VERSION 5.7 ;
  NOWIREEXTENSIONATPIN ON ;
  DIVIDERCHAR "/" ;
  BUSBITCHARS "[]" ;
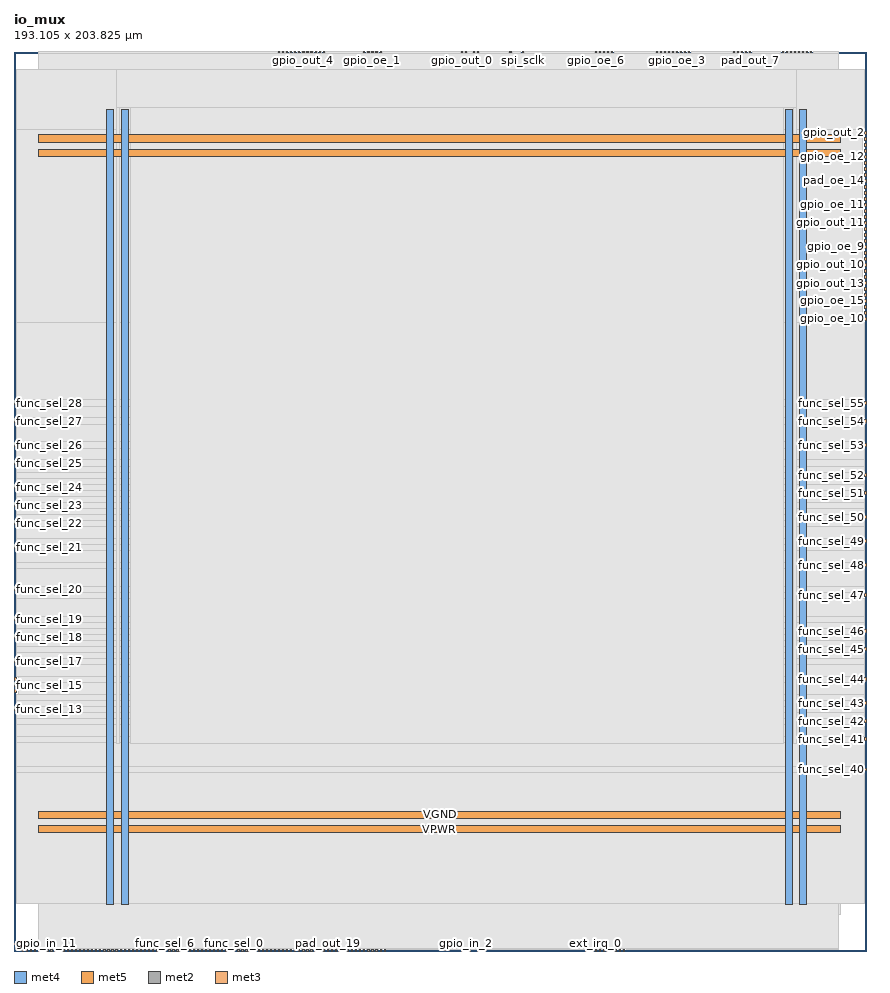
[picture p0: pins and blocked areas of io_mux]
MACRO io_mux
  CLASS BLOCK ;
  FOREIGN io_mux ;
  ORIGIN 0.000 0.000 ;
  SIZE 193.105 BY 203.825 ;
  PIN VGND
    DIRECTION INOUT ;
    USE GROUND ;
    PORT
      LAYER met4 ;
        RECT 24.340 10.640 25.940 190.640 ;
    END
    PORT
      LAYER met4 ;
        RECT 177.940 10.640 179.540 190.640 ;
    END
    PORT
      LAYER met5 ;
        RECT 5.520 30.030 187.220 31.630 ;
    END
    PORT
      LAYER met5 ;
        RECT 5.520 183.210 187.220 184.810 ;
    END
  END VGND
  PIN VPWR
    DIRECTION INOUT ;
    USE POWER ;
    PORT
      LAYER met4 ;
        RECT 21.040 10.640 22.640 190.640 ;
    END
    PORT
      LAYER met4 ;
        RECT 174.640 10.640 176.240 190.640 ;
    END
    PORT
      LAYER met5 ;
        RECT 5.520 26.730 187.220 28.330 ;
    END
    PORT
      LAYER met5 ;
        RECT 5.520 179.910 187.220 181.510 ;
    END
  END VPWR
  PIN ext_irq_0
    DIRECTION OUTPUT ;
    USE SIGNAL ;
    ANTENNAGATEAREA 0.434700 ;
    ANTENNADIFFAREA 0.775300 ;
    PORT
      LAYER met2 ;
        RECT 131.650 0.000 131.930 0.280 ;
    END
  END ext_irq_0
  PIN ext_irq_1
    DIRECTION OUTPUT ;
    USE SIGNAL ;
    ANTENNAGATEAREA 0.434700 ;
    ANTENNADIFFAREA 0.775300 ;
    PORT
      LAYER met2 ;
        RECT 138.090 0.000 138.370 0.280 ;
    END
  END ext_irq_1
  PIN ext_irq_2
    DIRECTION OUTPUT ;
    USE SIGNAL ;
    ANTENNAGATEAREA 0.434700 ;
    ANTENNADIFFAREA 0.775300 ;
    PORT
      LAYER met2 ;
        RECT 137.170 0.000 137.450 0.280 ;
    END
  END ext_irq_2
  PIN ext_irq_3
    DIRECTION OUTPUT ;
    USE SIGNAL ;
    ANTENNAGATEAREA 0.434700 ;
    ANTENNADIFFAREA 0.775300 ;
    PORT
      LAYER met2 ;
        RECT 133.490 0.000 133.770 0.280 ;
    END
  END ext_irq_3
  PIN ext_irq_4
    DIRECTION OUTPUT ;
    USE SIGNAL ;
    ANTENNAGATEAREA 0.434700 ;
    ANTENNADIFFAREA 0.775300 ;
    PORT
      LAYER met2 ;
        RECT 132.570 0.000 132.850 0.280 ;
    END
  END ext_irq_4
  PIN ext_irq_5
    DIRECTION OUTPUT ;
    USE SIGNAL ;
    ANTENNAGATEAREA 0.434700 ;
    ANTENNADIFFAREA 0.775300 ;
    PORT
      LAYER met2 ;
        RECT 134.410 0.000 134.690 0.280 ;
    END
  END ext_irq_5
  PIN ext_irq_6
    DIRECTION OUTPUT ;
    USE SIGNAL ;
    ANTENNAGATEAREA 0.434700 ;
    ANTENNADIFFAREA 0.775300 ;
    PORT
      LAYER met2 ;
        RECT 136.250 0.000 136.530 0.280 ;
    END
  END ext_irq_6
  PIN ext_irq_7
    DIRECTION OUTPUT ;
    USE SIGNAL ;
    ANTENNAGATEAREA 0.434700 ;
    ANTENNADIFFAREA 0.775300 ;
    PORT
      LAYER met2 ;
        RECT 135.330 0.000 135.610 0.280 ;
    END
  END ext_irq_7
  PIN func_sel_0
    DIRECTION INPUT ;
    USE SIGNAL ;
    ANTENNAGATEAREA 0.647700 ;
    ANTENNADIFFAREA 0.434700 ;
    PORT
      LAYER met2 ;
        RECT 49.770 0.000 50.050 0.280 ;
    END
  END func_sel_0
  PIN func_sel_1
    DIRECTION INPUT ;
    USE SIGNAL ;
    ANTENNAGATEAREA 0.647700 ;
    ANTENNADIFFAREA 0.434700 ;
    PORT
      LAYER met2 ;
        RECT 33.210 0.000 33.490 0.280 ;
    END
  END func_sel_1
  PIN func_sel_10
    DIRECTION INPUT ;
    USE SIGNAL ;
    ANTENNAGATEAREA 1.424700 ;
    ANTENNADIFFAREA 0.434700 ;
    PORT
      LAYER met2 ;
        RECT 23.090 0.000 23.370 0.280 ;
    END
  END func_sel_10
  PIN func_sel_11
    DIRECTION INPUT ;
    USE SIGNAL ;
    ANTENNAGATEAREA 1.424700 ;
    ANTENNADIFFAREA 0.434700 ;
    PORT
      LAYER met2 ;
        RECT 20.330 0.000 20.610 0.280 ;
    END
  END func_sel_11
  PIN func_sel_12
    DIRECTION INPUT ;
    USE SIGNAL ;
    ANTENNAGATEAREA 0.929700 ;
    ANTENNADIFFAREA 0.434700 ;
    PORT
      LAYER met2 ;
        RECT 18.490 0.000 18.770 0.280 ;
    END
  END func_sel_12
  PIN func_sel_13
    DIRECTION INPUT ;
    USE SIGNAL ;
    ANTENNAGATEAREA 0.929700 ;
    ANTENNADIFFAREA 0.434700 ;
    PORT
      LAYER met3 ;
        RECT 0.000 54.440 0.600 55.040 ;
    END
  END func_sel_13
  PIN func_sel_14
    DIRECTION INPUT ;
    USE SIGNAL ;
    ANTENNAGATEAREA 0.929700 ;
    ANTENNADIFFAREA 0.434700 ;
    PORT
      LAYER met3 ;
        RECT 0.000 61.240 0.600 61.840 ;
    END
  END func_sel_14
  PIN func_sel_15
    DIRECTION INPUT ;
    USE SIGNAL ;
    ANTENNAGATEAREA 0.647700 ;
    ANTENNADIFFAREA 0.434700 ;
    PORT
      LAYER met3 ;
        RECT 0.000 59.880 0.600 60.480 ;
    END
  END func_sel_15
  PIN func_sel_16
    DIRECTION INPUT ;
    USE SIGNAL ;
    ANTENNAGATEAREA 0.560700 ;
    ANTENNADIFFAREA 0.434700 ;
    PORT
      LAYER met3 ;
        RECT 0.000 58.520 0.600 59.120 ;
    END
  END func_sel_16
  PIN func_sel_17
    DIRECTION INPUT ;
    USE SIGNAL ;
    ANTENNAGATEAREA 0.647700 ;
    ANTENNADIFFAREA 0.434700 ;
    PORT
      LAYER met3 ;
        RECT 0.000 65.320 0.600 65.920 ;
    END
  END func_sel_17
  PIN func_sel_18
    DIRECTION INPUT ;
    USE SIGNAL ;
    ANTENNAGATEAREA 0.929700 ;
    ANTENNADIFFAREA 0.434700 ;
    PORT
      LAYER met3 ;
        RECT 0.000 70.760 0.600 71.360 ;
    END
  END func_sel_18
  PIN func_sel_19
    DIRECTION INPUT ;
    USE SIGNAL ;
    ANTENNAGATEAREA 0.647700 ;
    ANTENNADIFFAREA 0.434700 ;
    PORT
      LAYER met3 ;
        RECT 0.000 74.840 0.600 75.440 ;
    END
  END func_sel_19
  PIN func_sel_2
    DIRECTION INPUT ;
    USE SIGNAL ;
    ANTENNAGATEAREA 0.647700 ;
    ANTENNADIFFAREA 0.434700 ;
    PORT
      LAYER met2 ;
        RECT 42.410 0.000 42.690 0.280 ;
    END
  END func_sel_2
  PIN func_sel_20
    DIRECTION INPUT ;
    USE SIGNAL ;
    ANTENNAGATEAREA 0.929700 ;
    ANTENNADIFFAREA 0.434700 ;
    PORT
      LAYER met3 ;
        RECT 0.000 81.640 0.600 82.240 ;
    END
  END func_sel_20
  PIN func_sel_21
    DIRECTION INPUT ;
    USE SIGNAL ;
    ANTENNAGATEAREA 0.929700 ;
    ANTENNADIFFAREA 0.434700 ;
    PORT
      LAYER met3 ;
        RECT 0.000 91.160 0.600 91.760 ;
    END
  END func_sel_21
  PIN func_sel_22
    DIRECTION INPUT ;
    USE SIGNAL ;
    ANTENNAGATEAREA 0.682200 ;
    ANTENNADIFFAREA 0.434700 ;
    PORT
      LAYER met3 ;
        RECT 0.000 96.600 0.600 97.200 ;
    END
  END func_sel_22
  PIN func_sel_23
    DIRECTION INPUT ;
    USE SIGNAL ;
    ANTENNAGATEAREA 0.682200 ;
    ANTENNADIFFAREA 0.434700 ;
    PORT
      LAYER met3 ;
        RECT 0.000 100.680 0.600 101.280 ;
    END
  END func_sel_23
  PIN func_sel_24
    DIRECTION INPUT ;
    USE SIGNAL ;
    ANTENNAGATEAREA 0.593700 ;
    ANTENNADIFFAREA 0.434700 ;
    PORT
      LAYER met3 ;
        RECT 0.000 104.760 0.600 105.360 ;
    END
  END func_sel_24
  PIN func_sel_25
    DIRECTION INPUT ;
    USE SIGNAL ;
    ANTENNAGATEAREA 0.682200 ;
    ANTENNADIFFAREA 0.434700 ;
    PORT
      LAYER met3 ;
        RECT 0.000 110.200 0.600 110.800 ;
    END
  END func_sel_25
  PIN func_sel_26
    DIRECTION INPUT ;
    USE SIGNAL ;
    ANTENNAGATEAREA 0.682200 ;
    ANTENNADIFFAREA 0.434700 ;
    PORT
      LAYER met3 ;
        RECT 0.000 114.280 0.600 114.880 ;
    END
  END func_sel_26
  PIN func_sel_27
    DIRECTION INPUT ;
    USE SIGNAL ;
    ANTENNAGATEAREA 0.647700 ;
    ANTENNADIFFAREA 0.434700 ;
    PORT
      LAYER met3 ;
        RECT 0.000 119.720 0.600 120.320 ;
    END
  END func_sel_27
  PIN func_sel_28
    DIRECTION INPUT ;
    USE SIGNAL ;
    ANTENNAGATEAREA 0.929700 ;
    ANTENNADIFFAREA 0.434700 ;
    PORT
      LAYER met3 ;
        RECT 0.000 123.800 0.600 124.400 ;
    END
  END func_sel_28
  PIN func_sel_29
    DIRECTION INPUT ;
    USE SIGNAL ;
    ANTENNAGATEAREA 1.424700 ;
    ANTENNADIFFAREA 0.434700 ;
    PORT
      LAYER met2 ;
        RECT 35.050 0.000 35.330 0.280 ;
    END
  END func_sel_29
  PIN func_sel_3
    DIRECTION INPUT ;
    USE SIGNAL ;
    ANTENNAGATEAREA 0.929700 ;
    ANTENNADIFFAREA 0.434700 ;
    PORT
      LAYER met2 ;
        RECT 28.610 0.000 28.890 0.280 ;
    END
  END func_sel_3
  PIN func_sel_30
    DIRECTION INPUT ;
    USE SIGNAL ;
    ANTENNAGATEAREA 0.929700 ;
    ANTENNADIFFAREA 0.434700 ;
    PORT
      LAYER met2 ;
        RECT 39.650 0.000 39.930 0.280 ;
    END
  END func_sel_30
  PIN func_sel_31
    DIRECTION INPUT ;
    USE SIGNAL ;
    ANTENNAGATEAREA 0.929700 ;
    ANTENNADIFFAREA 0.434700 ;
    PORT
      LAYER met2 ;
        RECT 44.250 0.000 44.530 0.280 ;
    END
  END func_sel_31
  PIN func_sel_32
    DIRECTION INPUT ;
    USE SIGNAL ;
    ANTENNAGATEAREA 0.647700 ;
    ANTENNADIFFAREA 0.434700 ;
    PORT
      LAYER met2 ;
        RECT 47.930 0.000 48.210 0.280 ;
    END
  END func_sel_32
  PIN func_sel_33
    DIRECTION INPUT ;
    USE SIGNAL ;
    ANTENNAGATEAREA 0.647700 ;
    ANTENNADIFFAREA 0.434700 ;
    PORT
      LAYER met2 ;
        RECT 51.610 0.000 51.890 0.280 ;
    END
  END func_sel_33
  PIN func_sel_34
    DIRECTION INPUT ;
    USE SIGNAL ;
    ANTENNAGATEAREA 0.682200 ;
    ANTENNADIFFAREA 0.434700 ;
    PORT
      LAYER met2 ;
        RECT 55.290 0.000 55.570 0.280 ;
    END
  END func_sel_34
  PIN func_sel_35
    DIRECTION INPUT ;
    USE SIGNAL ;
    ANTENNAGATEAREA 0.647700 ;
    ANTENNADIFFAREA 0.434700 ;
    PORT
      LAYER met2 ;
        RECT 59.890 0.000 60.170 0.280 ;
    END
  END func_sel_35
  PIN func_sel_36
    DIRECTION INPUT ;
    USE SIGNAL ;
    ANTENNAGATEAREA 0.647700 ;
    ANTENNADIFFAREA 0.434700 ;
    PORT
      LAYER met2 ;
        RECT 63.570 0.000 63.850 0.280 ;
    END
  END func_sel_36
  PIN func_sel_37
    DIRECTION INPUT ;
    USE SIGNAL ;
    ANTENNAGATEAREA 0.560700 ;
    ANTENNADIFFAREA 0.434700 ;
    PORT
      LAYER met2 ;
        RECT 67.250 0.000 67.530 0.280 ;
    END
  END func_sel_37
  PIN func_sel_38
    DIRECTION INPUT ;
    USE SIGNAL ;
    ANTENNAGATEAREA 0.560700 ;
    ANTENNADIFFAREA 0.434700 ;
    PORT
      LAYER met2 ;
        RECT 70.010 0.000 70.290 0.280 ;
    END
  END func_sel_38
  PIN func_sel_39
    DIRECTION INPUT ;
    USE SIGNAL ;
    ANTENNAGATEAREA 0.647700 ;
    ANTENNADIFFAREA 0.434700 ;
    PORT
      LAYER met2 ;
        RECT 73.690 0.000 73.970 0.280 ;
    END
  END func_sel_39
  PIN func_sel_4
    DIRECTION INPUT ;
    USE SIGNAL ;
    ANTENNAGATEAREA 0.929700 ;
    ANTENNADIFFAREA 0.434700 ;
    PORT
      LAYER met2 ;
        RECT 43.330 0.000 43.610 0.280 ;
    END
  END func_sel_4
  PIN func_sel_40
    DIRECTION INPUT ;
    USE SIGNAL ;
    ANTENNAGATEAREA 0.647700 ;
    ANTENNADIFFAREA 0.434700 ;
    PORT
      LAYER met3 ;
        RECT 192.505 40.840 193.105 41.440 ;
    END
  END func_sel_40
  PIN func_sel_41
    DIRECTION INPUT ;
    USE SIGNAL ;
    ANTENNAGATEAREA 0.647700 ;
    ANTENNADIFFAREA 0.434700 ;
    PORT
      LAYER met3 ;
        RECT 192.505 47.640 193.105 48.240 ;
    END
  END func_sel_41
  PIN func_sel_42
    DIRECTION INPUT ;
    USE SIGNAL ;
    ANTENNAGATEAREA 0.647700 ;
    ANTENNADIFFAREA 0.434700 ;
    PORT
      LAYER met3 ;
        RECT 192.505 51.720 193.105 52.320 ;
    END
  END func_sel_42
  PIN func_sel_43
    DIRECTION INPUT ;
    USE SIGNAL ;
    ANTENNAGATEAREA 0.647700 ;
    ANTENNADIFFAREA 0.434700 ;
    PORT
      LAYER met3 ;
        RECT 192.505 55.800 193.105 56.400 ;
    END
  END func_sel_43
  PIN func_sel_44
    DIRECTION INPUT ;
    USE SIGNAL ;
    ANTENNAGATEAREA 0.647700 ;
    ANTENNADIFFAREA 0.434700 ;
    PORT
      LAYER met3 ;
        RECT 192.505 61.240 193.105 61.840 ;
    END
  END func_sel_44
  PIN func_sel_45
    DIRECTION INPUT ;
    USE SIGNAL ;
    ANTENNAGATEAREA 0.647700 ;
    ANTENNADIFFAREA 0.434700 ;
    PORT
      LAYER met3 ;
        RECT 192.505 68.040 193.105 68.640 ;
    END
  END func_sel_45
  PIN func_sel_46
    DIRECTION INPUT ;
    USE SIGNAL ;
    ANTENNAGATEAREA 0.647700 ;
    ANTENNADIFFAREA 0.434700 ;
    PORT
      LAYER met3 ;
        RECT 192.505 72.120 193.105 72.720 ;
    END
  END func_sel_46
  PIN func_sel_47
    DIRECTION INPUT ;
    USE SIGNAL ;
    ANTENNAGATEAREA 0.647700 ;
    ANTENNADIFFAREA 0.434700 ;
    PORT
      LAYER met3 ;
        RECT 192.505 80.280 193.105 80.880 ;
    END
  END func_sel_47
  PIN func_sel_48
    DIRECTION INPUT ;
    USE SIGNAL ;
    ANTENNAGATEAREA 0.647700 ;
    ANTENNADIFFAREA 0.434700 ;
    PORT
      LAYER met3 ;
        RECT 192.505 87.080 193.105 87.680 ;
    END
  END func_sel_48
  PIN func_sel_49
    DIRECTION INPUT ;
    USE SIGNAL ;
    ANTENNAGATEAREA 0.647700 ;
    ANTENNADIFFAREA 0.434700 ;
    PORT
      LAYER met3 ;
        RECT 192.505 92.520 193.105 93.120 ;
    END
  END func_sel_49
  PIN func_sel_5
    DIRECTION INPUT ;
    USE SIGNAL ;
    ANTENNAGATEAREA 0.929700 ;
    ANTENNADIFFAREA 0.434700 ;
    PORT
      LAYER met2 ;
        RECT 41.490 0.000 41.770 0.280 ;
    END
  END func_sel_5
  PIN func_sel_50
    DIRECTION INPUT ;
    USE SIGNAL ;
    ANTENNAGATEAREA 0.647700 ;
    ANTENNADIFFAREA 0.434700 ;
    PORT
      LAYER met3 ;
        RECT 192.505 97.960 193.105 98.560 ;
    END
  END func_sel_50
  PIN func_sel_51
    DIRECTION INPUT ;
    USE SIGNAL ;
    ANTENNAGATEAREA 0.647700 ;
    ANTENNADIFFAREA 0.434700 ;
    PORT
      LAYER met3 ;
        RECT 192.505 103.400 193.105 104.000 ;
    END
  END func_sel_51
  PIN func_sel_52
    DIRECTION INPUT ;
    USE SIGNAL ;
    ANTENNAGATEAREA 0.647700 ;
    ANTENNADIFFAREA 0.434700 ;
    PORT
      LAYER met3 ;
        RECT 192.505 107.480 193.105 108.080 ;
    END
  END func_sel_52
  PIN func_sel_53
    DIRECTION INPUT ;
    USE SIGNAL ;
    ANTENNAGATEAREA 0.647700 ;
    ANTENNADIFFAREA 0.434700 ;
    PORT
      LAYER met3 ;
        RECT 192.505 114.280 193.105 114.880 ;
    END
  END func_sel_53
  PIN func_sel_54
    DIRECTION INPUT ;
    USE SIGNAL ;
    ANTENNAGATEAREA 0.647700 ;
    ANTENNADIFFAREA 0.434700 ;
    PORT
      LAYER met3 ;
        RECT 192.505 119.720 193.105 120.320 ;
    END
  END func_sel_54
  PIN func_sel_55
    DIRECTION INPUT ;
    USE SIGNAL ;
    ANTENNAGATEAREA 0.647700 ;
    ANTENNADIFFAREA 0.434700 ;
    PORT
      LAYER met3 ;
        RECT 192.505 123.800 193.105 124.400 ;
    END
  END func_sel_55
  PIN func_sel_56
    DIRECTION INPUT ;
    USE SIGNAL ;
    ANTENNAGATEAREA 0.647700 ;
    ANTENNADIFFAREA 0.434700 ;
    PORT
      LAYER met2 ;
        RECT 180.410 203.545 180.690 203.825 ;
    END
  END func_sel_56
  PIN func_sel_57
    DIRECTION INPUT ;
    USE SIGNAL ;
    ANTENNAGATEAREA 0.647700 ;
    ANTENNADIFFAREA 0.434700 ;
    PORT
      LAYER met2 ;
        RECT 179.490 203.545 179.770 203.825 ;
    END
  END func_sel_57
  PIN func_sel_58
    DIRECTION INPUT ;
    USE SIGNAL ;
    ANTENNAGATEAREA 0.647700 ;
    ANTENNADIFFAREA 0.434700 ;
    PORT
      LAYER met2 ;
        RECT 178.570 203.545 178.850 203.825 ;
    END
  END func_sel_58
  PIN func_sel_59
    DIRECTION INPUT ;
    USE SIGNAL ;
    ANTENNAGATEAREA 0.647700 ;
    ANTENNADIFFAREA 0.434700 ;
    PORT
      LAYER met2 ;
        RECT 177.650 203.545 177.930 203.825 ;
    END
  END func_sel_59
  PIN func_sel_6
    DIRECTION INPUT ;
    USE SIGNAL ;
    ANTENNAGATEAREA 0.682200 ;
    ANTENNADIFFAREA 0.434700 ;
    PORT
      LAYER met2 ;
        RECT 34.130 0.000 34.410 0.280 ;
    END
  END func_sel_6
  PIN func_sel_60
    DIRECTION INPUT ;
    USE SIGNAL ;
    ANTENNAGATEAREA 0.647700 ;
    ANTENNADIFFAREA 0.434700 ;
    PORT
      LAYER met2 ;
        RECT 176.730 203.545 177.010 203.825 ;
    END
  END func_sel_60
  PIN func_sel_61
    DIRECTION INPUT ;
    USE SIGNAL ;
    ANTENNAGATEAREA 0.647700 ;
    ANTENNADIFFAREA 0.434700 ;
    PORT
      LAYER met2 ;
        RECT 175.810 203.545 176.090 203.825 ;
    END
  END func_sel_61
  PIN func_sel_62
    DIRECTION INPUT ;
    USE SIGNAL ;
    ANTENNAGATEAREA 0.647700 ;
    ANTENNADIFFAREA 0.434700 ;
    PORT
      LAYER met2 ;
        RECT 174.890 203.545 175.170 203.825 ;
    END
  END func_sel_62
  PIN func_sel_63
    DIRECTION INPUT ;
    USE SIGNAL ;
    ANTENNAGATEAREA 0.647700 ;
    ANTENNADIFFAREA 0.434700 ;
    PORT
      LAYER met2 ;
        RECT 173.970 203.545 174.250 203.825 ;
    END
  END func_sel_63
  PIN func_sel_7
    DIRECTION INPUT ;
    USE SIGNAL ;
    ANTENNAGATEAREA 0.682200 ;
    ANTENNADIFFAREA 0.434700 ;
    PORT
      LAYER met2 ;
        RECT 35.970 0.000 36.250 0.280 ;
    END
  END func_sel_7
  PIN func_sel_8
    DIRECTION INPUT ;
    USE SIGNAL ;
    ANTENNAGATEAREA 0.929700 ;
    ANTENNADIFFAREA 0.434700 ;
    PORT
      LAYER met2 ;
        RECT 26.770 0.000 27.050 0.280 ;
    END
  END func_sel_8
  PIN func_sel_9
    DIRECTION INPUT ;
    USE SIGNAL ;
    ANTENNAGATEAREA 0.647700 ;
    ANTENNADIFFAREA 0.434700 ;
    PORT
      LAYER met2 ;
        RECT 24.930 0.000 25.210 0.280 ;
    END
  END func_sel_9
  PIN gpio_in_0
    DIRECTION OUTPUT ;
    USE SIGNAL ;
    PORT
      LAYER met2 ;
        RECT 1.930 0.000 2.210 0.280 ;
    END
  END gpio_in_0
  PIN gpio_in_1
    DIRECTION OUTPUT ;
    USE SIGNAL ;
    PORT
      LAYER met2 ;
        RECT 2.850 0.000 3.130 0.280 ;
    END
  END gpio_in_1
  PIN gpio_in_10
    DIRECTION OUTPUT ;
    USE SIGNAL ;
    PORT
      LAYER met2 ;
        RECT 3.770 0.000 4.050 0.280 ;
    END
  END gpio_in_10
  PIN gpio_in_11
    DIRECTION OUTPUT ;
    USE SIGNAL ;
    PORT
      LAYER met2 ;
        RECT 4.690 0.000 4.970 0.280 ;
    END
  END gpio_in_11
  PIN gpio_in_12
    DIRECTION OUTPUT ;
    USE SIGNAL ;
    PORT
      LAYER met2 ;
        RECT 5.610 0.000 5.890 0.280 ;
    END
  END gpio_in_12
  PIN gpio_in_13
    DIRECTION OUTPUT ;
    USE SIGNAL ;
    PORT
      LAYER met2 ;
        RECT 6.530 0.000 6.810 0.280 ;
    END
  END gpio_in_13
  PIN gpio_in_14
    DIRECTION OUTPUT ;
    USE SIGNAL ;
    PORT
      LAYER met2 ;
        RECT 7.450 0.000 7.730 0.280 ;
    END
  END gpio_in_14
  PIN gpio_in_15
    DIRECTION OUTPUT ;
    USE SIGNAL ;
    PORT
      LAYER met2 ;
        RECT 8.370 0.000 8.650 0.280 ;
    END
  END gpio_in_15
  PIN gpio_in_16
    DIRECTION OUTPUT ;
    USE SIGNAL ;
    PORT
      LAYER met2 ;
        RECT 9.290 0.000 9.570 0.280 ;
    END
  END gpio_in_16
  PIN gpio_in_17
    DIRECTION OUTPUT ;
    USE SIGNAL ;
    PORT
      LAYER met2 ;
        RECT 10.210 0.000 10.490 0.280 ;
    END
  END gpio_in_17
  PIN gpio_in_18
    DIRECTION OUTPUT ;
    USE SIGNAL ;
    PORT
      LAYER met2 ;
        RECT 11.130 0.000 11.410 0.280 ;
    END
  END gpio_in_18
  PIN gpio_in_19
    DIRECTION OUTPUT ;
    USE SIGNAL ;
    PORT
      LAYER met2 ;
        RECT 12.050 0.000 12.330 0.280 ;
    END
  END gpio_in_19
  PIN gpio_in_2
    DIRECTION OUTPUT ;
    USE SIGNAL ;
    ANTENNAGATEAREA 0.434700 ;
    ANTENNADIFFAREA 1.137600 ;
    PORT
      LAYER met2 ;
        RECT 102.210 0.000 102.490 0.280 ;
    END
  END gpio_in_2
  PIN gpio_in_20
    DIRECTION OUTPUT ;
    USE SIGNAL ;
    PORT
      LAYER met2 ;
        RECT 12.970 0.000 13.250 0.280 ;
    END
  END gpio_in_20
  PIN gpio_in_21
    DIRECTION OUTPUT ;
    USE SIGNAL ;
    PORT
      LAYER met2 ;
        RECT 13.890 0.000 14.170 0.280 ;
    END
  END gpio_in_21
  PIN gpio_in_22
    DIRECTION OUTPUT ;
    USE SIGNAL ;
    PORT
      LAYER met2 ;
        RECT 14.810 0.000 15.090 0.280 ;
    END
  END gpio_in_22
  PIN gpio_in_23
    DIRECTION OUTPUT ;
    USE SIGNAL ;
    PORT
      LAYER met2 ;
        RECT 15.730 0.000 16.010 0.280 ;
    END
  END gpio_in_23
  PIN gpio_in_24
    DIRECTION OUTPUT ;
    USE SIGNAL ;
    PORT
      LAYER met2 ;
        RECT 16.650 0.000 16.930 0.280 ;
    END
  END gpio_in_24
  PIN gpio_in_25
    DIRECTION OUTPUT ;
    USE SIGNAL ;
    PORT
      LAYER met2 ;
        RECT 17.570 0.000 17.850 0.280 ;
    END
  END gpio_in_25
  PIN gpio_in_26
    DIRECTION OUTPUT ;
    USE SIGNAL ;
    PORT
      LAYER met2 ;
        RECT 19.410 0.000 19.690 0.280 ;
    END
  END gpio_in_26
  PIN gpio_in_27
    DIRECTION OUTPUT ;
    USE SIGNAL ;
    PORT
      LAYER met2 ;
        RECT 21.250 0.000 21.530 0.280 ;
    END
  END gpio_in_27
  PIN gpio_in_28
    DIRECTION OUTPUT ;
    USE SIGNAL ;
    PORT
      LAYER met2 ;
        RECT 22.170 0.000 22.450 0.280 ;
    END
  END gpio_in_28
  PIN gpio_in_29
    DIRECTION OUTPUT ;
    USE SIGNAL ;
    PORT
      LAYER met2 ;
        RECT 24.010 0.000 24.290 0.280 ;
    END
  END gpio_in_29
  PIN gpio_in_3
    DIRECTION OUTPUT ;
    USE SIGNAL ;
    PORT
      LAYER met2 ;
        RECT 25.850 0.000 26.130 0.280 ;
    END
  END gpio_in_3
  PIN gpio_in_30
    DIRECTION OUTPUT ;
    USE SIGNAL ;
    PORT
      LAYER met2 ;
        RECT 27.690 0.000 27.970 0.280 ;
    END
  END gpio_in_30
  PIN gpio_in_31
    DIRECTION OUTPUT ;
    USE SIGNAL ;
    PORT
      LAYER met2 ;
        RECT 29.530 0.000 29.810 0.280 ;
    END
  END gpio_in_31
  PIN gpio_in_4
    DIRECTION OUTPUT ;
    USE SIGNAL ;
    PORT
      LAYER met2 ;
        RECT 30.450 0.000 30.730 0.280 ;
    END
  END gpio_in_4
  PIN gpio_in_5
    DIRECTION OUTPUT ;
    USE SIGNAL ;
    PORT
      LAYER met2 ;
        RECT 31.370 0.000 31.650 0.280 ;
    END
  END gpio_in_5
  PIN gpio_in_6
    DIRECTION OUTPUT ;
    USE SIGNAL ;
    PORT
      LAYER met2 ;
        RECT 32.290 0.000 32.570 0.280 ;
    END
  END gpio_in_6
  PIN gpio_in_7
    DIRECTION OUTPUT ;
    USE SIGNAL ;
    PORT
      LAYER met2 ;
        RECT 36.890 0.000 37.170 0.280 ;
    END
  END gpio_in_7
  PIN gpio_in_8
    DIRECTION OUTPUT ;
    USE SIGNAL ;
    PORT
      LAYER met2 ;
        RECT 37.810 0.000 38.090 0.280 ;
    END
  END gpio_in_8
  PIN gpio_in_9
    DIRECTION OUTPUT ;
    USE SIGNAL ;
    PORT
      LAYER met2 ;
        RECT 38.730 0.000 39.010 0.280 ;
    END
  END gpio_in_9
  PIN gpio_oe_0
    DIRECTION INPUT ;
    USE SIGNAL ;
    ANTENNAGATEAREA 0.647700 ;
    ANTENNADIFFAREA 0.434700 ;
    PORT
      LAYER met2 ;
        RECT 104.970 203.545 105.250 203.825 ;
    END
  END gpio_oe_0
  PIN gpio_oe_1
    DIRECTION INPUT ;
    USE SIGNAL ;
    ANTENNAGATEAREA 0.647700 ;
    ANTENNADIFFAREA 0.434700 ;
    PORT
      LAYER met2 ;
        RECT 81.050 203.545 81.330 203.825 ;
    END
  END gpio_oe_1
  PIN gpio_oe_10
    DIRECTION INPUT ;
    USE SIGNAL ;
    ANTENNAGATEAREA 0.647700 ;
    ANTENNADIFFAREA 0.434700 ;
    PORT
      LAYER met3 ;
        RECT 192.505 142.840 193.105 143.440 ;
    END
  END gpio_oe_10
  PIN gpio_oe_11
    DIRECTION INPUT ;
    USE SIGNAL ;
    ANTENNAGATEAREA 0.647700 ;
    ANTENNADIFFAREA 0.434700 ;
    PORT
      LAYER met3 ;
        RECT 192.505 168.680 193.105 169.280 ;
    END
  END gpio_oe_11
  PIN gpio_oe_12
    DIRECTION INPUT ;
    USE SIGNAL ;
    ANTENNAGATEAREA 0.647700 ;
    ANTENNADIFFAREA 0.434700 ;
    PORT
      LAYER met3 ;
        RECT 192.505 179.560 193.105 180.160 ;
    END
  END gpio_oe_12
  PIN gpio_oe_13
    DIRECTION INPUT ;
    USE SIGNAL ;
    ANTENNAGATEAREA 0.647700 ;
    ANTENNADIFFAREA 0.434700 ;
    PORT
      LAYER met3 ;
        RECT 192.505 149.640 193.105 150.240 ;
    END
  END gpio_oe_13
  PIN gpio_oe_14
    DIRECTION INPUT ;
    USE SIGNAL ;
    ANTENNAGATEAREA 0.647700 ;
    ANTENNADIFFAREA 0.434700 ;
    PORT
      LAYER met3 ;
        RECT 192.505 172.760 193.105 173.360 ;
    END
  END gpio_oe_14
  PIN gpio_oe_15
    DIRECTION INPUT ;
    USE SIGNAL ;
    ANTENNAGATEAREA 0.647700 ;
    ANTENNADIFFAREA 0.434700 ;
    PORT
      LAYER met3 ;
        RECT 192.505 145.560 193.105 146.160 ;
    END
  END gpio_oe_15
  PIN gpio_oe_2
    DIRECTION INPUT ;
    USE SIGNAL ;
    ANTENNAGATEAREA 0.647700 ;
    ANTENNADIFFAREA 0.434700 ;
    PORT
      LAYER met3 ;
        RECT 192.505 180.920 193.105 181.520 ;
    END
  END gpio_oe_2
  PIN gpio_oe_3
    DIRECTION INPUT ;
    USE SIGNAL ;
    ANTENNAGATEAREA 0.647700 ;
    ANTENNADIFFAREA 0.434700 ;
    PORT
      LAYER met2 ;
        RECT 150.050 203.545 150.330 203.825 ;
    END
  END gpio_oe_3
  PIN gpio_oe_4
    DIRECTION INPUT ;
    USE SIGNAL ;
    ANTENNAGATEAREA 0.647700 ;
    ANTENNADIFFAREA 0.434700 ;
    PORT
      LAYER met2 ;
        RECT 69.090 203.545 69.370 203.825 ;
    END
  END gpio_oe_4
  PIN gpio_oe_5
    DIRECTION INPUT ;
    USE SIGNAL ;
    ANTENNAGATEAREA 0.647700 ;
    ANTENNADIFFAREA 0.434700 ;
    PORT
      LAYER met2 ;
        RECT 67.250 203.545 67.530 203.825 ;
    END
  END gpio_oe_5
  PIN gpio_oe_6
    DIRECTION INPUT ;
    USE SIGNAL ;
    ANTENNAGATEAREA 0.647700 ;
    ANTENNADIFFAREA 0.434700 ;
    PORT
      LAYER met2 ;
        RECT 131.650 203.545 131.930 203.825 ;
    END
  END gpio_oe_6
  PIN gpio_oe_7
    DIRECTION INPUT ;
    USE SIGNAL ;
    ANTENNAGATEAREA 0.647700 ;
    ANTENNADIFFAREA 0.434700 ;
    PORT
      LAYER met2 ;
        RECT 165.690 203.545 165.970 203.825 ;
    END
  END gpio_oe_7
  PIN gpio_oe_8
    DIRECTION INPUT ;
    USE SIGNAL ;
    ANTENNAGATEAREA 0.647700 ;
    ANTENNADIFFAREA 0.434700 ;
    PORT
      LAYER met2 ;
        RECT 148.210 203.545 148.490 203.825 ;
    END
  END gpio_oe_8
  PIN gpio_oe_9
    DIRECTION INPUT ;
    USE SIGNAL ;
    ANTENNAGATEAREA 0.647700 ;
    ANTENNADIFFAREA 0.434700 ;
    PORT
      LAYER met3 ;
        RECT 192.505 159.160 193.105 159.760 ;
    END
  END gpio_oe_9
  PIN gpio_out_0
    DIRECTION INPUT ;
    USE SIGNAL ;
    ANTENNAGATEAREA 0.647700 ;
    ANTENNADIFFAREA 0.434700 ;
    PORT
      LAYER met2 ;
        RECT 101.290 203.545 101.570 203.825 ;
    END
  END gpio_out_0
  PIN gpio_out_1
    DIRECTION INPUT ;
    USE SIGNAL ;
    ANTENNAGATEAREA 0.647700 ;
    ANTENNADIFFAREA 0.434700 ;
    PORT
      LAYER met2 ;
        RECT 82.890 203.545 83.170 203.825 ;
    END
  END gpio_out_1
  PIN gpio_out_10
    DIRECTION INPUT ;
    USE SIGNAL ;
    ANTENNAGATEAREA 0.647700 ;
    ANTENNADIFFAREA 0.434700 ;
    PORT
      LAYER met3 ;
        RECT 192.505 155.080 193.105 155.680 ;
    END
  END gpio_out_10
  PIN gpio_out_11
    DIRECTION INPUT ;
    USE SIGNAL ;
    ANTENNAGATEAREA 0.647700 ;
    ANTENNADIFFAREA 0.434700 ;
    PORT
      LAYER met3 ;
        RECT 192.505 164.600 193.105 165.200 ;
    END
  END gpio_out_11
  PIN gpio_out_12
    DIRECTION INPUT ;
    USE SIGNAL ;
    ANTENNAGATEAREA 0.647700 ;
    ANTENNADIFFAREA 0.434700 ;
    PORT
      LAYER met3 ;
        RECT 192.505 178.200 193.105 178.800 ;
    END
  END gpio_out_12
  PIN gpio_out_13
    DIRECTION INPUT ;
    USE SIGNAL ;
    ANTENNAGATEAREA 0.647700 ;
    ANTENNADIFFAREA 0.434700 ;
    PORT
      LAYER met3 ;
        RECT 192.505 152.360 193.105 152.960 ;
    END
  END gpio_out_13
  PIN gpio_out_14
    DIRECTION INPUT ;
    USE SIGNAL ;
    ANTENNAGATEAREA 0.647700 ;
    ANTENNADIFFAREA 0.434700 ;
    PORT
      LAYER met3 ;
        RECT 192.505 170.040 193.105 170.640 ;
    END
  END gpio_out_14
  PIN gpio_out_15
    DIRECTION INPUT ;
    USE SIGNAL ;
    ANTENNAGATEAREA 0.647700 ;
    ANTENNADIFFAREA 0.434700 ;
    PORT
      LAYER met3 ;
        RECT 192.505 156.440 193.105 157.040 ;
    END
  END gpio_out_15
  PIN gpio_out_2
    DIRECTION INPUT ;
    USE SIGNAL ;
    ANTENNAGATEAREA 0.647700 ;
    ANTENNADIFFAREA 0.434700 ;
    PORT
      LAYER met3 ;
        RECT 192.505 185.000 193.105 185.600 ;
    END
  END gpio_out_2
  PIN gpio_out_3
    DIRECTION INPUT ;
    USE SIGNAL ;
    ANTENNAGATEAREA 0.647700 ;
    ANTENNADIFFAREA 0.434700 ;
    PORT
      LAYER met2 ;
        RECT 152.810 203.545 153.090 203.825 ;
    END
  END gpio_out_3
  PIN gpio_out_4
    DIRECTION INPUT ;
    USE SIGNAL ;
    ANTENNAGATEAREA 0.647700 ;
    ANTENNADIFFAREA 0.434700 ;
    PORT
      LAYER met2 ;
        RECT 65.410 203.545 65.690 203.825 ;
    END
  END gpio_out_4
  PIN gpio_out_5
    DIRECTION INPUT ;
    USE SIGNAL ;
    ANTENNAGATEAREA 0.647700 ;
    ANTENNADIFFAREA 0.434700 ;
    PORT
      LAYER met2 ;
        RECT 66.330 203.545 66.610 203.825 ;
    END
  END gpio_out_5
  PIN gpio_out_6
    DIRECTION INPUT ;
    USE SIGNAL ;
    ANTENNAGATEAREA 0.647700 ;
    ANTENNADIFFAREA 0.434700 ;
    PORT
      LAYER met2 ;
        RECT 134.410 203.545 134.690 203.825 ;
    END
  END gpio_out_6
  PIN gpio_out_7
    DIRECTION INPUT ;
    USE SIGNAL ;
    ANTENNAGATEAREA 0.647700 ;
    ANTENNADIFFAREA 0.434700 ;
    PORT
      LAYER met2 ;
        RECT 164.770 203.545 165.050 203.825 ;
    END
  END gpio_out_7
  PIN gpio_out_8
    DIRECTION INPUT ;
    USE SIGNAL ;
    ANTENNAGATEAREA 0.647700 ;
    ANTENNADIFFAREA 0.434700 ;
    PORT
      LAYER met2 ;
        RECT 149.130 203.545 149.410 203.825 ;
    END
  END gpio_out_8
  PIN gpio_out_9
    DIRECTION INPUT ;
    USE SIGNAL ;
    ANTENNAGATEAREA 0.647700 ;
    ANTENNADIFFAREA 0.434700 ;
    PORT
      LAYER met3 ;
        RECT 192.505 160.520 193.105 161.120 ;
    END
  END gpio_out_9
  PIN i2c_scl_in
    DIRECTION OUTPUT ;
    USE SIGNAL ;
    PORT
      LAYER met2 ;
        RECT 40.570 0.000 40.850 0.280 ;
    END
  END i2c_scl_in
  PIN i2c_scl_oe
    DIRECTION INPUT ;
    USE SIGNAL ;
    ANTENNAGATEAREA 0.647700 ;
    ANTENNADIFFAREA 0.434700 ;
    PORT
      LAYER met2 ;
        RECT 59.890 203.545 60.170 203.825 ;
    END
  END i2c_scl_oe
  PIN i2c_scl_out
    DIRECTION INPUT ;
    USE SIGNAL ;
    ANTENNAGATEAREA 0.647700 ;
    ANTENNADIFFAREA 0.434700 ;
    PORT
      LAYER met2 ;
        RECT 61.730 203.545 62.010 203.825 ;
    END
  END i2c_scl_out
  PIN i2c_sda_in
    DIRECTION OUTPUT ;
    USE SIGNAL ;
    PORT
      LAYER met2 ;
        RECT 45.170 0.000 45.450 0.280 ;
    END
  END i2c_sda_in
  PIN i2c_sda_oe
    DIRECTION INPUT ;
    USE SIGNAL ;
    ANTENNAGATEAREA 0.647700 ;
    ANTENNADIFFAREA 0.434700 ;
    PORT
      LAYER met2 ;
        RECT 60.810 203.545 61.090 203.825 ;
    END
  END i2c_sda_oe
  PIN i2c_sda_out
    DIRECTION INPUT ;
    USE SIGNAL ;
    ANTENNAGATEAREA 0.647700 ;
    ANTENNADIFFAREA 0.434700 ;
    PORT
      LAYER met2 ;
        RECT 62.650 203.545 62.930 203.825 ;
    END
  END i2c_sda_out
  PIN pad_oe_0
    DIRECTION OUTPUT ;
    USE SIGNAL ;
    ANTENNAGATEAREA 0.434700 ;
    ANTENNADIFFAREA 1.771200 ;
    PORT
      LAYER met2 ;
        RECT 104.050 203.545 104.330 203.825 ;
    END
  END pad_oe_0
  PIN pad_oe_1
    DIRECTION OUTPUT ;
    USE SIGNAL ;
    ANTENNAGATEAREA 0.434700 ;
    ANTENNADIFFAREA 1.771200 ;
    PORT
      LAYER met2 ;
        RECT 79.210 203.545 79.490 203.825 ;
    END
  END pad_oe_1
  PIN pad_oe_10
    DIRECTION OUTPUT ;
    USE SIGNAL ;
    ANTENNAGATEAREA 0.434700 ;
    ANTENNADIFFAREA 2.216700 ;
    PORT
      LAYER met3 ;
        RECT 192.505 148.280 193.105 148.880 ;
    END
  END pad_oe_10
  PIN pad_oe_11
    DIRECTION OUTPUT ;
    USE SIGNAL ;
    ANTENNAGATEAREA 0.434700 ;
    ANTENNADIFFAREA 2.216700 ;
    PORT
      LAYER met3 ;
        RECT 192.505 167.320 193.105 167.920 ;
    END
  END pad_oe_11
  PIN pad_oe_12
    DIRECTION OUTPUT ;
    USE SIGNAL ;
    ANTENNAGATEAREA 0.434700 ;
    ANTENNADIFFAREA 1.325700 ;
    PORT
      LAYER met3 ;
        RECT 192.505 175.480 193.105 176.080 ;
    END
  END pad_oe_12
  PIN pad_oe_13
    DIRECTION OUTPUT ;
    USE SIGNAL ;
    ANTENNAGATEAREA 0.434700 ;
    ANTENNADIFFAREA 2.216700 ;
    PORT
      LAYER met3 ;
        RECT 192.505 151.000 193.105 151.600 ;
    END
  END pad_oe_13
  PIN pad_oe_14
    DIRECTION OUTPUT ;
    USE SIGNAL ;
    ANTENNAGATEAREA 0.434700 ;
    ANTENNADIFFAREA 2.216700 ;
    PORT
      LAYER met3 ;
        RECT 192.505 174.120 193.105 174.720 ;
    END
  END pad_oe_14
  PIN pad_oe_15
    DIRECTION OUTPUT ;
    USE SIGNAL ;
    ANTENNAGATEAREA 0.434700 ;
    ANTENNADIFFAREA 1.325700 ;
    PORT
      LAYER met3 ;
        RECT 192.505 144.200 193.105 144.800 ;
    END
  END pad_oe_15
  PIN pad_oe_16
    DIRECTION OUTPUT ;
    USE SIGNAL ;
    PORT
      LAYER met2 ;
        RECT 46.090 0.000 46.370 0.280 ;
    END
  END pad_oe_16
  PIN pad_oe_17
    DIRECTION OUTPUT ;
    USE SIGNAL ;
    PORT
      LAYER met2 ;
        RECT 47.010 0.000 47.290 0.280 ;
    END
  END pad_oe_17
  PIN pad_oe_18
    DIRECTION OUTPUT ;
    USE SIGNAL ;
    PORT
      LAYER met2 ;
        RECT 48.850 0.000 49.130 0.280 ;
    END
  END pad_oe_18
  PIN pad_oe_19
    DIRECTION OUTPUT ;
    USE SIGNAL ;
    PORT
      LAYER met2 ;
        RECT 50.690 0.000 50.970 0.280 ;
    END
  END pad_oe_19
  PIN pad_oe_2
    DIRECTION OUTPUT ;
    USE SIGNAL ;
    ANTENNAGATEAREA 0.434700 ;
    ANTENNADIFFAREA 1.771200 ;
    PORT
      LAYER met3 ;
        RECT 192.505 182.280 193.105 182.880 ;
    END
  END pad_oe_2
  PIN pad_oe_20
    DIRECTION OUTPUT ;
    USE SIGNAL ;
    PORT
      LAYER met2 ;
        RECT 52.530 0.000 52.810 0.280 ;
    END
  END pad_oe_20
  PIN pad_oe_21
    DIRECTION OUTPUT ;
    USE SIGNAL ;
    PORT
      LAYER met2 ;
        RECT 53.450 0.000 53.730 0.280 ;
    END
  END pad_oe_21
  PIN pad_oe_22
    DIRECTION OUTPUT ;
    USE SIGNAL ;
    PORT
      LAYER met2 ;
        RECT 54.370 0.000 54.650 0.280 ;
    END
  END pad_oe_22
  PIN pad_oe_23
    DIRECTION OUTPUT ;
    USE SIGNAL ;
    PORT
      LAYER met2 ;
        RECT 56.210 0.000 56.490 0.280 ;
    END
  END pad_oe_23
  PIN pad_oe_24
    DIRECTION OUTPUT ;
    USE SIGNAL ;
    PORT
      LAYER met2 ;
        RECT 57.130 0.000 57.410 0.280 ;
    END
  END pad_oe_24
  PIN pad_oe_25
    DIRECTION OUTPUT ;
    USE SIGNAL ;
    PORT
      LAYER met2 ;
        RECT 58.050 0.000 58.330 0.280 ;
    END
  END pad_oe_25
  PIN pad_oe_26
    DIRECTION OUTPUT ;
    USE SIGNAL ;
    PORT
      LAYER met2 ;
        RECT 58.970 0.000 59.250 0.280 ;
    END
  END pad_oe_26
  PIN pad_oe_27
    DIRECTION OUTPUT ;
    USE SIGNAL ;
    PORT
      LAYER met2 ;
        RECT 60.810 0.000 61.090 0.280 ;
    END
  END pad_oe_27
  PIN pad_oe_28
    DIRECTION OUTPUT ;
    USE SIGNAL ;
    PORT
      LAYER met2 ;
        RECT 61.730 0.000 62.010 0.280 ;
    END
  END pad_oe_28
  PIN pad_oe_29
    DIRECTION OUTPUT ;
    USE SIGNAL ;
    PORT
      LAYER met2 ;
        RECT 62.650 0.000 62.930 0.280 ;
    END
  END pad_oe_29
  PIN pad_oe_3
    DIRECTION OUTPUT ;
    USE SIGNAL ;
    ANTENNAGATEAREA 0.434700 ;
    ANTENNADIFFAREA 1.771200 ;
    PORT
      LAYER met2 ;
        RECT 145.450 203.545 145.730 203.825 ;
    END
  END pad_oe_3
  PIN pad_oe_30
    DIRECTION OUTPUT ;
    USE SIGNAL ;
    PORT
      LAYER met2 ;
        RECT 64.490 0.000 64.770 0.280 ;
    END
  END pad_oe_30
  PIN pad_oe_31
    DIRECTION OUTPUT ;
    USE SIGNAL ;
    PORT
      LAYER met2 ;
        RECT 65.410 0.000 65.690 0.280 ;
    END
  END pad_oe_31
  PIN pad_oe_4
    DIRECTION OUTPUT ;
    USE SIGNAL ;
    ANTENNAGATEAREA 0.434700 ;
    ANTENNADIFFAREA 1.771200 ;
    PORT
      LAYER met2 ;
        RECT 63.570 203.545 63.850 203.825 ;
    END
  END pad_oe_4
  PIN pad_oe_5
    DIRECTION OUTPUT ;
    USE SIGNAL ;
    ANTENNAGATEAREA 0.434700 ;
    ANTENNADIFFAREA 1.771200 ;
    PORT
      LAYER met2 ;
        RECT 68.170 203.545 68.450 203.825 ;
    END
  END pad_oe_5
  PIN pad_oe_6
    DIRECTION OUTPUT ;
    USE SIGNAL ;
    ANTENNAGATEAREA 0.434700 ;
    ANTENNADIFFAREA 1.771200 ;
    PORT
      LAYER met2 ;
        RECT 132.570 203.545 132.850 203.825 ;
    END
  END pad_oe_6
  PIN pad_oe_7
    DIRECTION OUTPUT ;
    USE SIGNAL ;
    ANTENNAGATEAREA 0.434700 ;
    ANTENNADIFFAREA 1.771200 ;
    PORT
      LAYER met2 ;
        RECT 162.930 203.545 163.210 203.825 ;
    END
  END pad_oe_7
  PIN pad_oe_8
    DIRECTION OUTPUT ;
    USE SIGNAL ;
    ANTENNAGATEAREA 0.434700 ;
    ANTENNADIFFAREA 1.771200 ;
    PORT
      LAYER met2 ;
        RECT 146.370 203.545 146.650 203.825 ;
    END
  END pad_oe_8
  PIN pad_oe_9
    DIRECTION OUTPUT ;
    USE SIGNAL ;
    ANTENNAGATEAREA 0.434700 ;
    ANTENNADIFFAREA 1.771200 ;
    PORT
      LAYER met3 ;
        RECT 192.505 161.880 193.105 162.480 ;
    END
  END pad_oe_9
  PIN pad_out_0
    DIRECTION OUTPUT ;
    USE SIGNAL ;
    ANTENNAGATEAREA 0.434700 ;
    ANTENNADIFFAREA 1.771200 ;
    PORT
      LAYER met2 ;
        RECT 102.210 203.545 102.490 203.825 ;
    END
  END pad_out_0
  PIN pad_out_1
    DIRECTION OUTPUT ;
    USE SIGNAL ;
    ANTENNAGATEAREA 0.434700 ;
    ANTENNADIFFAREA 1.771200 ;
    PORT
      LAYER met2 ;
        RECT 81.970 203.545 82.250 203.825 ;
    END
  END pad_out_1
  PIN pad_out_10
    DIRECTION OUTPUT ;
    USE SIGNAL ;
    ANTENNAGATEAREA 0.434700 ;
    ANTENNADIFFAREA 1.771200 ;
    PORT
      LAYER met3 ;
        RECT 192.505 146.920 193.105 147.520 ;
    END
  END pad_out_10
  PIN pad_out_11
    DIRECTION OUTPUT ;
    USE SIGNAL ;
    ANTENNAGATEAREA 0.434700 ;
    ANTENNADIFFAREA 2.216700 ;
    PORT
      LAYER met3 ;
        RECT 192.505 165.960 193.105 166.560 ;
    END
  END pad_out_11
  PIN pad_out_12
    DIRECTION OUTPUT ;
    USE SIGNAL ;
    ANTENNAGATEAREA 0.434700 ;
    ANTENNADIFFAREA 2.216700 ;
    PORT
      LAYER met3 ;
        RECT 192.505 176.840 193.105 177.440 ;
    END
  END pad_out_12
  PIN pad_out_13
    DIRECTION OUTPUT ;
    USE SIGNAL ;
    ANTENNAGATEAREA 0.434700 ;
    ANTENNADIFFAREA 2.216700 ;
    PORT
      LAYER met3 ;
        RECT 192.505 153.720 193.105 154.320 ;
    END
  END pad_out_13
  PIN pad_out_14
    DIRECTION OUTPUT ;
    USE SIGNAL ;
    ANTENNAGATEAREA 0.434700 ;
    ANTENNADIFFAREA 2.216700 ;
    PORT
      LAYER met3 ;
        RECT 192.505 171.400 193.105 172.000 ;
    END
  END pad_out_14
  PIN pad_out_15
    DIRECTION OUTPUT ;
    USE SIGNAL ;
    ANTENNAGATEAREA 0.434700 ;
    ANTENNADIFFAREA 1.325700 ;
    PORT
      LAYER met3 ;
        RECT 192.505 157.800 193.105 158.400 ;
    END
  END pad_out_15
  PIN pad_out_16
    DIRECTION OUTPUT ;
    USE SIGNAL ;
    PORT
      LAYER met2 ;
        RECT 66.330 0.000 66.610 0.280 ;
    END
  END pad_out_16
  PIN pad_out_17
    DIRECTION OUTPUT ;
    USE SIGNAL ;
    PORT
      LAYER met2 ;
        RECT 68.170 0.000 68.450 0.280 ;
    END
  END pad_out_17
  PIN pad_out_18
    DIRECTION OUTPUT ;
    USE SIGNAL ;
    PORT
      LAYER met2 ;
        RECT 69.090 0.000 69.370 0.280 ;
    END
  END pad_out_18
  PIN pad_out_19
    DIRECTION OUTPUT ;
    USE SIGNAL ;
    PORT
      LAYER met2 ;
        RECT 70.930 0.000 71.210 0.280 ;
    END
  END pad_out_19
  PIN pad_out_2
    DIRECTION OUTPUT ;
    USE SIGNAL ;
    ANTENNAGATEAREA 0.434700 ;
    ANTENNADIFFAREA 2.216700 ;
    PORT
      LAYER met3 ;
        RECT 192.505 183.640 193.105 184.240 ;
    END
  END pad_out_2
  PIN pad_out_20
    DIRECTION OUTPUT ;
    USE SIGNAL ;
    PORT
      LAYER met2 ;
        RECT 71.850 0.000 72.130 0.280 ;
    END
  END pad_out_20
  PIN pad_out_21
    DIRECTION OUTPUT ;
    USE SIGNAL ;
    PORT
      LAYER met2 ;
        RECT 72.770 0.000 73.050 0.280 ;
    END
  END pad_out_21
  PIN pad_out_22
    DIRECTION OUTPUT ;
    USE SIGNAL ;
    PORT
      LAYER met2 ;
        RECT 74.610 0.000 74.890 0.280 ;
    END
  END pad_out_22
  PIN pad_out_23
    DIRECTION OUTPUT ;
    USE SIGNAL ;
    PORT
      LAYER met2 ;
        RECT 75.530 0.000 75.810 0.280 ;
    END
  END pad_out_23
  PIN pad_out_24
    DIRECTION OUTPUT ;
    USE SIGNAL ;
    PORT
      LAYER met2 ;
        RECT 76.450 0.000 76.730 0.280 ;
    END
  END pad_out_24
  PIN pad_out_25
    DIRECTION OUTPUT ;
    USE SIGNAL ;
    PORT
      LAYER met2 ;
        RECT 77.370 0.000 77.650 0.280 ;
    END
  END pad_out_25
  PIN pad_out_26
    DIRECTION OUTPUT ;
    USE SIGNAL ;
    PORT
      LAYER met2 ;
        RECT 78.290 0.000 78.570 0.280 ;
    END
  END pad_out_26
  PIN pad_out_27
    DIRECTION OUTPUT ;
    USE SIGNAL ;
    PORT
      LAYER met2 ;
        RECT 79.210 0.000 79.490 0.280 ;
    END
  END pad_out_27
  PIN pad_out_28
    DIRECTION OUTPUT ;
    USE SIGNAL ;
    PORT
      LAYER met2 ;
        RECT 80.130 0.000 80.410 0.280 ;
    END
  END pad_out_28
  PIN pad_out_29
    DIRECTION OUTPUT ;
    USE SIGNAL ;
    PORT
      LAYER met2 ;
        RECT 81.050 0.000 81.330 0.280 ;
    END
  END pad_out_29
  PIN pad_out_3
    DIRECTION OUTPUT ;
    USE SIGNAL ;
    ANTENNAGATEAREA 0.434700 ;
    ANTENNADIFFAREA 1.771200 ;
    PORT
      LAYER met2 ;
        RECT 151.890 203.545 152.170 203.825 ;
    END
  END pad_out_3
  PIN pad_out_30
    DIRECTION OUTPUT ;
    USE SIGNAL ;
    PORT
      LAYER met2 ;
        RECT 81.970 0.000 82.250 0.280 ;
    END
  END pad_out_30
  PIN pad_out_31
    DIRECTION OUTPUT ;
    USE SIGNAL ;
    PORT
      LAYER met2 ;
        RECT 82.890 0.000 83.170 0.280 ;
    END
  END pad_out_31
  PIN pad_out_4
    DIRECTION OUTPUT ;
    USE SIGNAL ;
    ANTENNAGATEAREA 0.434700 ;
    ANTENNADIFFAREA 1.771200 ;
    PORT
      LAYER met2 ;
        RECT 64.490 203.545 64.770 203.825 ;
    END
  END pad_out_4
  PIN pad_out_5
    DIRECTION OUTPUT ;
    USE SIGNAL ;
    ANTENNAGATEAREA 0.434700 ;
    ANTENNADIFFAREA 1.771200 ;
    PORT
      LAYER met2 ;
        RECT 70.010 203.545 70.290 203.825 ;
    END
  END pad_out_5
  PIN pad_out_6
    DIRECTION OUTPUT ;
    USE SIGNAL ;
    ANTENNAGATEAREA 0.434700 ;
    ANTENNADIFFAREA 1.771200 ;
    PORT
      LAYER met2 ;
        RECT 135.330 203.545 135.610 203.825 ;
    END
  END pad_out_6
  PIN pad_out_7
    DIRECTION OUTPUT ;
    USE SIGNAL ;
    ANTENNAGATEAREA 0.434700 ;
    ANTENNADIFFAREA 1.771200 ;
    PORT
      LAYER met2 ;
        RECT 166.610 203.545 166.890 203.825 ;
    END
  END pad_out_7
  PIN pad_out_8
    DIRECTION OUTPUT ;
    USE SIGNAL ;
    ANTENNAGATEAREA 0.434700 ;
    ANTENNADIFFAREA 2.216700 ;
    PORT
      LAYER met2 ;
        RECT 147.290 203.545 147.570 203.825 ;
    END
  END pad_out_8
  PIN pad_out_9
    DIRECTION OUTPUT ;
    USE SIGNAL ;
    ANTENNAGATEAREA 0.434700 ;
    ANTENNADIFFAREA 2.216700 ;
    PORT
      LAYER met3 ;
        RECT 192.505 163.240 193.105 163.840 ;
    END
  END pad_out_9
  PIN spi_cs_n
    DIRECTION INPUT ;
    USE SIGNAL ;
    ANTENNAGATEAREA 0.647700 ;
    ANTENNADIFFAREA 0.434700 ;
    PORT
      LAYER met2 ;
        RECT 150.970 203.545 151.250 203.825 ;
    END
  END spi_cs_n
  PIN spi_miso
    DIRECTION OUTPUT ;
    USE SIGNAL ;
    ANTENNAGATEAREA 0.434700 ;
    ANTENNADIFFAREA 1.137600 ;
    PORT
      LAYER met2 ;
        RECT 103.130 0.000 103.410 0.280 ;
    END
  END spi_miso
  PIN spi_mosi
    DIRECTION INPUT ;
    USE SIGNAL ;
    ANTENNAGATEAREA 0.647700 ;
    ANTENNADIFFAREA 0.434700 ;
    PORT
      LAYER met2 ;
        RECT 80.130 203.545 80.410 203.825 ;
    END
  END spi_mosi
  PIN spi_sclk
    DIRECTION INPUT ;
    USE SIGNAL ;
    ANTENNAGATEAREA 1.424700 ;
    ANTENNADIFFAREA 0.434700 ;
    PORT
      LAYER met2 ;
        RECT 115.090 203.545 115.370 203.825 ;
    END
  END spi_sclk
  PIN timer_out
    DIRECTION INPUT ;
    USE SIGNAL ;
    ANTENNAGATEAREA 0.647700 ;
    ANTENNADIFFAREA 0.434700 ;
    PORT
      LAYER met2 ;
        RECT 133.490 203.545 133.770 203.825 ;
    END
  END timer_out
  PIN uart_rx
    DIRECTION OUTPUT ;
    USE SIGNAL ;
    PORT
      LAYER met2 ;
        RECT 83.810 0.000 84.090 0.280 ;
    END
  END uart_rx
  PIN uart_tx
    DIRECTION INPUT ;
    USE SIGNAL ;
    ANTENNAGATEAREA 0.647700 ;
    ANTENNADIFFAREA 0.434700 ;
    PORT
      LAYER met2 ;
        RECT 112.330 203.545 112.610 203.825 ;
    END
  END uart_tx
  PIN wdt_reset_out
    DIRECTION INPUT ;
    USE SIGNAL ;
    ANTENNAGATEAREA 0.647700 ;
    ANTENNADIFFAREA 0.434700 ;
    PORT
      LAYER met2 ;
        RECT 163.850 203.545 164.130 203.825 ;
    END
  END wdt_reset_out
  OBS
      LAYER nwell ;
        RECT 5.330 10.795 187.410 190.485 ;
      LAYER li1 ;
        RECT 5.520 10.795 187.220 190.485 ;
      LAYER met1 ;
        RECT 5.520 8.200 187.220 198.860 ;
      LAYER met2 ;
        RECT 5.610 203.265 59.610 203.730 ;
        RECT 60.450 203.265 60.530 203.730 ;
        RECT 61.370 203.265 61.450 203.730 ;
        RECT 62.290 203.265 62.370 203.730 ;
        RECT 63.210 203.265 63.290 203.730 ;
        RECT 64.130 203.265 64.210 203.730 ;
        RECT 65.050 203.265 65.130 203.730 ;
        RECT 65.970 203.265 66.050 203.730 ;
        RECT 66.890 203.265 66.970 203.730 ;
        RECT 67.810 203.265 67.890 203.730 ;
        RECT 68.730 203.265 68.810 203.730 ;
        RECT 69.650 203.265 69.730 203.730 ;
        RECT 70.570 203.265 78.930 203.730 ;
        RECT 79.770 203.265 79.850 203.730 ;
        RECT 80.690 203.265 80.770 203.730 ;
        RECT 81.610 203.265 81.690 203.730 ;
        RECT 82.530 203.265 82.610 203.730 ;
        RECT 83.450 203.265 101.010 203.730 ;
        RECT 101.850 203.265 101.930 203.730 ;
        RECT 102.770 203.265 103.770 203.730 ;
        RECT 104.610 203.265 104.690 203.730 ;
        RECT 105.530 203.265 112.050 203.730 ;
        RECT 112.890 203.265 114.810 203.730 ;
        RECT 115.650 203.265 131.370 203.730 ;
        RECT 132.210 203.265 132.290 203.730 ;
        RECT 133.130 203.265 133.210 203.730 ;
        RECT 134.050 203.265 134.130 203.730 ;
        RECT 134.970 203.265 135.050 203.730 ;
        RECT 135.890 203.265 145.170 203.730 ;
        RECT 146.010 203.265 146.090 203.730 ;
        RECT 146.930 203.265 147.010 203.730 ;
        RECT 147.850 203.265 147.930 203.730 ;
        RECT 148.770 203.265 148.850 203.730 ;
        RECT 149.690 203.265 149.770 203.730 ;
        RECT 150.610 203.265 150.690 203.730 ;
        RECT 151.530 203.265 151.610 203.730 ;
        RECT 152.450 203.265 152.530 203.730 ;
        RECT 153.370 203.265 162.650 203.730 ;
        RECT 163.490 203.265 163.570 203.730 ;
        RECT 164.410 203.265 164.490 203.730 ;
        RECT 165.330 203.265 165.410 203.730 ;
        RECT 166.250 203.265 166.330 203.730 ;
        RECT 167.170 203.265 173.690 203.730 ;
        RECT 174.530 203.265 174.610 203.730 ;
        RECT 175.450 203.265 175.530 203.730 ;
        RECT 176.370 203.265 176.450 203.730 ;
        RECT 177.290 203.265 177.370 203.730 ;
        RECT 178.210 203.265 178.290 203.730 ;
        RECT 179.130 203.265 179.210 203.730 ;
        RECT 180.050 203.265 180.130 203.730 ;
        RECT 180.970 203.265 186.670 203.730 ;
        RECT 5.610 0.560 186.670 203.265 ;
        RECT 6.170 0.280 6.250 0.560 ;
        RECT 7.090 0.280 7.170 0.560 ;
        RECT 8.010 0.280 8.090 0.560 ;
        RECT 8.930 0.280 9.010 0.560 ;
        RECT 9.850 0.280 9.930 0.560 ;
        RECT 10.770 0.280 10.850 0.560 ;
        RECT 11.690 0.280 11.770 0.560 ;
        RECT 12.610 0.280 12.690 0.560 ;
        RECT 13.530 0.280 13.610 0.560 ;
        RECT 14.450 0.280 14.530 0.560 ;
        RECT 15.370 0.280 15.450 0.560 ;
        RECT 16.290 0.280 16.370 0.560 ;
        RECT 17.210 0.280 17.290 0.560 ;
        RECT 18.130 0.280 18.210 0.560 ;
        RECT 19.050 0.280 19.130 0.560 ;
        RECT 19.970 0.280 20.050 0.560 ;
        RECT 20.890 0.280 20.970 0.560 ;
        RECT 21.810 0.280 21.890 0.560 ;
        RECT 22.730 0.280 22.810 0.560 ;
        RECT 23.650 0.280 23.730 0.560 ;
        RECT 24.570 0.280 24.650 0.560 ;
        RECT 25.490 0.280 25.570 0.560 ;
        RECT 26.410 0.280 26.490 0.560 ;
        RECT 27.330 0.280 27.410 0.560 ;
        RECT 28.250 0.280 28.330 0.560 ;
        RECT 29.170 0.280 29.250 0.560 ;
        RECT 30.090 0.280 30.170 0.560 ;
        RECT 31.010 0.280 31.090 0.560 ;
        RECT 31.930 0.280 32.010 0.560 ;
        RECT 32.850 0.280 32.930 0.560 ;
        RECT 33.770 0.280 33.850 0.560 ;
        RECT 34.690 0.280 34.770 0.560 ;
        RECT 35.610 0.280 35.690 0.560 ;
        RECT 36.530 0.280 36.610 0.560 ;
        RECT 37.450 0.280 37.530 0.560 ;
        RECT 38.370 0.280 38.450 0.560 ;
        RECT 39.290 0.280 39.370 0.560 ;
        RECT 40.210 0.280 40.290 0.560 ;
        RECT 41.130 0.280 41.210 0.560 ;
        RECT 42.050 0.280 42.130 0.560 ;
        RECT 42.970 0.280 43.050 0.560 ;
        RECT 43.890 0.280 43.970 0.560 ;
        RECT 44.810 0.280 44.890 0.560 ;
        RECT 45.730 0.280 45.810 0.560 ;
        RECT 46.650 0.280 46.730 0.560 ;
        RECT 47.570 0.280 47.650 0.560 ;
        RECT 48.490 0.280 48.570 0.560 ;
        RECT 49.410 0.280 49.490 0.560 ;
        RECT 50.330 0.280 50.410 0.560 ;
        RECT 51.250 0.280 51.330 0.560 ;
        RECT 52.170 0.280 52.250 0.560 ;
        RECT 53.090 0.280 53.170 0.560 ;
        RECT 54.010 0.280 54.090 0.560 ;
        RECT 54.930 0.280 55.010 0.560 ;
        RECT 55.850 0.280 55.930 0.560 ;
        RECT 56.770 0.280 56.850 0.560 ;
        RECT 57.690 0.280 57.770 0.560 ;
        RECT 58.610 0.280 58.690 0.560 ;
        RECT 59.530 0.280 59.610 0.560 ;
        RECT 60.450 0.280 60.530 0.560 ;
        RECT 61.370 0.280 61.450 0.560 ;
        RECT 62.290 0.280 62.370 0.560 ;
        RECT 63.210 0.280 63.290 0.560 ;
        RECT 64.130 0.280 64.210 0.560 ;
        RECT 65.050 0.280 65.130 0.560 ;
        RECT 65.970 0.280 66.050 0.560 ;
        RECT 66.890 0.280 66.970 0.560 ;
        RECT 67.810 0.280 67.890 0.560 ;
        RECT 68.730 0.280 68.810 0.560 ;
        RECT 69.650 0.280 69.730 0.560 ;
        RECT 70.570 0.280 70.650 0.560 ;
        RECT 71.490 0.280 71.570 0.560 ;
        RECT 72.410 0.280 72.490 0.560 ;
        RECT 73.330 0.280 73.410 0.560 ;
        RECT 74.250 0.280 74.330 0.560 ;
        RECT 75.170 0.280 75.250 0.560 ;
        RECT 76.090 0.280 76.170 0.560 ;
        RECT 77.010 0.280 77.090 0.560 ;
        RECT 77.930 0.280 78.010 0.560 ;
        RECT 78.850 0.280 78.930 0.560 ;
        RECT 79.770 0.280 79.850 0.560 ;
        RECT 80.690 0.280 80.770 0.560 ;
        RECT 81.610 0.280 81.690 0.560 ;
        RECT 82.530 0.280 82.610 0.560 ;
        RECT 83.450 0.280 83.530 0.560 ;
        RECT 84.370 0.280 101.930 0.560 ;
        RECT 102.770 0.280 102.850 0.560 ;
        RECT 103.690 0.280 131.370 0.560 ;
        RECT 132.210 0.280 132.290 0.560 ;
        RECT 133.130 0.280 133.210 0.560 ;
        RECT 134.050 0.280 134.130 0.560 ;
        RECT 134.970 0.280 135.050 0.560 ;
        RECT 135.890 0.280 135.970 0.560 ;
        RECT 136.810 0.280 136.890 0.560 ;
        RECT 137.730 0.280 137.810 0.560 ;
        RECT 138.650 0.280 186.670 0.560 ;
      LAYER met3 ;
        RECT 0.600 186.000 192.505 199.745 ;
        RECT 0.600 142.440 192.105 186.000 ;
        RECT 0.600 124.800 192.505 142.440 ;
        RECT 1.000 123.400 192.105 124.800 ;
        RECT 0.600 120.720 192.505 123.400 ;
        RECT 1.000 119.320 192.105 120.720 ;
        RECT 0.600 115.280 192.505 119.320 ;
        RECT 1.000 113.880 192.105 115.280 ;
        RECT 0.600 111.200 192.505 113.880 ;
        RECT 1.000 109.800 192.505 111.200 ;
        RECT 0.600 108.480 192.505 109.800 ;
        RECT 0.600 107.080 192.105 108.480 ;
        RECT 0.600 105.760 192.505 107.080 ;
        RECT 1.000 104.400 192.505 105.760 ;
        RECT 1.000 104.360 192.105 104.400 ;
        RECT 0.600 103.000 192.105 104.360 ;
        RECT 0.600 101.680 192.505 103.000 ;
        RECT 1.000 100.280 192.505 101.680 ;
        RECT 0.600 98.960 192.505 100.280 ;
        RECT 0.600 97.600 192.105 98.960 ;
        RECT 1.000 97.560 192.105 97.600 ;
        RECT 1.000 96.200 192.505 97.560 ;
        RECT 0.600 93.520 192.505 96.200 ;
        RECT 0.600 92.160 192.105 93.520 ;
        RECT 1.000 92.120 192.105 92.160 ;
        RECT 1.000 90.760 192.505 92.120 ;
        RECT 0.600 88.080 192.505 90.760 ;
        RECT 0.600 86.680 192.105 88.080 ;
        RECT 0.600 82.640 192.505 86.680 ;
        RECT 1.000 81.280 192.505 82.640 ;
        RECT 1.000 81.240 192.105 81.280 ;
        RECT 0.600 79.880 192.105 81.240 ;
        RECT 0.600 75.840 192.505 79.880 ;
        RECT 1.000 74.440 192.505 75.840 ;
        RECT 0.600 73.120 192.505 74.440 ;
        RECT 0.600 71.760 192.105 73.120 ;
        RECT 1.000 71.720 192.105 71.760 ;
        RECT 1.000 70.360 192.505 71.720 ;
        RECT 0.600 69.040 192.505 70.360 ;
        RECT 0.600 67.640 192.105 69.040 ;
        RECT 0.600 66.320 192.505 67.640 ;
        RECT 1.000 64.920 192.505 66.320 ;
        RECT 0.600 62.240 192.505 64.920 ;
        RECT 1.000 60.840 192.105 62.240 ;
        RECT 1.000 58.120 192.505 60.840 ;
        RECT 0.600 56.800 192.505 58.120 ;
        RECT 0.600 55.440 192.105 56.800 ;
        RECT 1.000 55.400 192.105 55.440 ;
        RECT 1.000 54.040 192.505 55.400 ;
        RECT 0.600 52.720 192.505 54.040 ;
        RECT 0.600 51.320 192.105 52.720 ;
        RECT 0.600 48.640 192.505 51.320 ;
        RECT 0.600 47.240 192.105 48.640 ;
        RECT 0.600 41.840 192.505 47.240 ;
        RECT 0.600 40.440 192.105 41.840 ;
        RECT 0.600 10.715 192.505 40.440 ;
      LAYER met4 ;
        RECT 23.295 191.040 177.265 199.745 ;
        RECT 23.295 47.095 23.940 191.040 ;
        RECT 26.340 47.095 174.240 191.040 ;
        RECT 176.640 47.095 177.265 191.040 ;
  END
END io_mux
END LIBRARY

